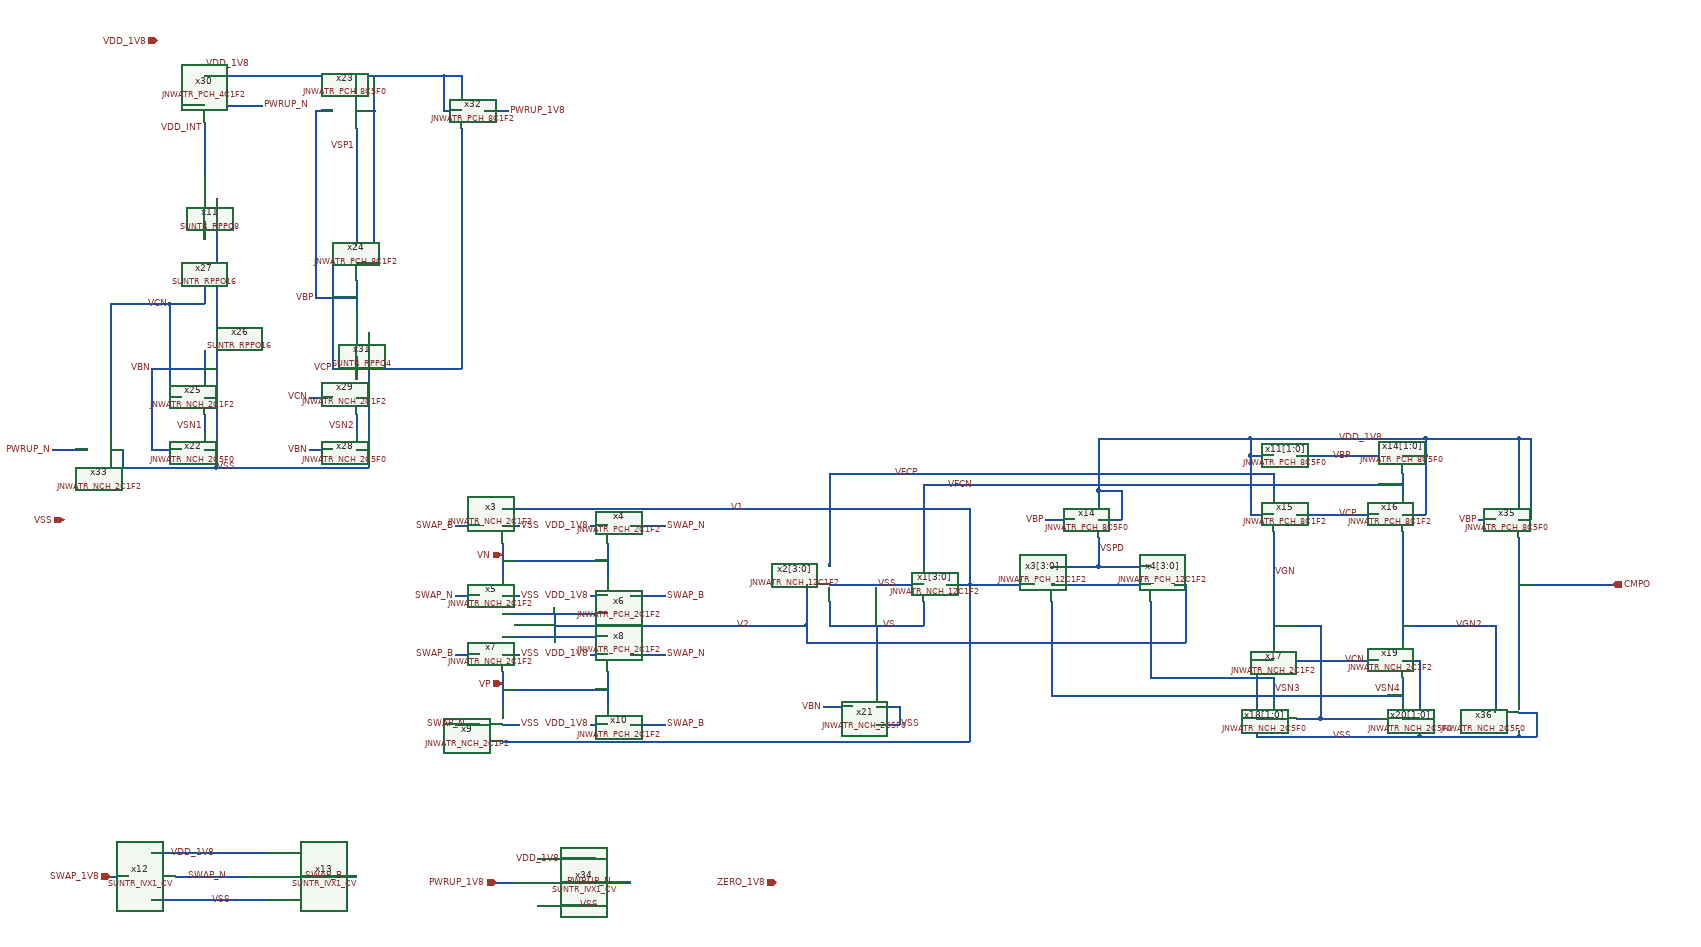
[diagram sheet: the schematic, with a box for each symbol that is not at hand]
v {xschem version=3.4.5 file_version=1.2
}
G {}
K {}
V {}
S {}
E {}
N 970 -730 1000 -730 {
lab=VSS}
N 1120 -730 1150 -730 {
lab=VDD_1V8}
N 890 -730 930 -730 {
lab=SWAP_B}
N 1190 -730 1250 -730 {
lab=SWAP_N}
N 970 -610 1000 -610 {
lab=VSS}
N 1120 -610 1150 -610 {
lab=VDD_1V8}
N 890 -610 930 -610 {
lab=SWAP_N}
N 1190 -610 1250 -610 {
lab=SWAP_B}
N 970 -700 970 -640 {
lab=VN}
N 1150 -700 1150 -640 {
lab=VN}
N 970 -580 1150 -580 {
lab=V2}
N 970 -760 1150 -760 {
lab=V1}
N 970 -510 1000 -510 {
lab=VSS}
N 1120 -510 1150 -510 {
lab=VDD_1V8}
N 890 -510 930 -510 {
lab=SWAP_B}
N 1190 -510 1250 -510 {
lab=SWAP_N}
N 970 -390 1000 -390 {
lab=VSS}
N 1120 -390 1150 -390 {
lab=VDD_1V8}
N 890 -390 930 -390 {
lab=SWAP_N}
N 1190 -390 1250 -390 {
lab=SWAP_B}
N 970 -480 970 -420 {
lab=VP}
N 1150 -480 1150 -420 {
lab=VP}
N 970 -360 1150 -360 {
lab=V1}
N 970 -540 1150 -540 {
lab=V2}
N 1060 -580 1060 -540 {
lab=V2}
N 1060 -560 1490 -560 {
lab=V2}
N 1490 -630 1490 -560 {
lab=V2}
N 1160 -760 1770 -760 {
lab=V1}
N 1770 -760 1770 -630 {
lab=V1}
N 1730 -630 1770 -630 {
lab=V1}
N 1150 -360 1770 -360 {
lab=V1}
N 1770 -630 1770 -360 {
lab=V1}
N 1530 -600 1530 -560 {
lab=VS}
N 1530 -560 1690 -560 {
lab=VS}
N 1690 -600 1690 -560 {
lab=VS}
N 370 -170 470 -170 {
lab=VDD_1V8}
N 370 -90 470 -90 {
lab=VSS}
N 410 -130 430 -130 {
lab=SWAP_N}
N 300 -130 330 -130 {
lab=SWAP_1V8}
N 470 -90 570 -90 {
lab=VSS}
N 470 -170 560 -170 {
lab=VDD_1V8}
N 430 -130 530 -130 {
lab=SWAP_N}
N 610 -130 720 -130 {
lab=SWAP_B}
N 970 -450 1150 -450 {
lab=VP}
N 970 -670 1150 -670 {
lab=VN}
N 1530 -630 1690 -630 {
lab=VSS}
N 2250 -850 2290 -850 {
lab=VDD_1V8}
N 2250 -880 2250 -850 {
lab=VDD_1V8}
N 2250 -880 2290 -880 {
lab=VDD_1V8}
N 2290 -880 2510 -880 {
lab=VDD_1V8}
N 2510 -850 2550 -850 {
lab=VDD_1V8}
N 2550 -880 2550 -850 {
lab=VDD_1V8}
N 2510 -880 2550 -880 {
lab=VDD_1V8}
N 2510 -820 2510 -780 {
lab=VFCN}
N 2290 -820 2290 -780 {
lab=VFCP}
N 2250 -750 2290 -750 {
lab=VDD_1V8}
N 2250 -850 2250 -750 {
lab=VDD_1V8}
N 2510 -750 2550 -750 {
lab=VDD_1V8}
N 2550 -850 2550 -750 {
lab=VDD_1V8}
N 2290 -470 2290 -430 {
lab=VSN3}
N 2260 -500 2290 -500 {
lab=VSS}
N 2260 -500 2260 -370 {
lab=VSS}
N 2260 -370 2290 -370 {
lab=VSS}
N 2260 -400 2290 -400 {
lab=VSS}
N 2510 -470 2510 -430 {
lab=VSN4}
N 2510 -500 2540 -500 {
lab=VSS}
N 2540 -500 2540 -370 {
lab=VSS}
N 2510 -370 2540 -370 {
lab=VSS}
N 2510 -400 2540 -400 {
lab=VSS}
N 2290 -720 2290 -530 {
lab=VGN}
N 2290 -370 2510 -370 {
lab=VSS}
N 1690 -800 1690 -660 {
lab=VFCN}
N 1690 -800 2130 -800 {
lab=VFCN}
N 1530 -820 1530 -660 {
lab=VFCP}
N 1530 -820 1910 -820 {
lab=VFCP}
N 2330 -400 2370 -400 {
lab=VGN}
N 2370 -560 2370 -400 {
lab=VGN}
N 2290 -560 2370 -560 {
lab=VGN}
N 2330 -500 2470 -500 {
lab=VCN}
N 2330 -750 2470 -750 {
lab=VCP}
N 2330 -850 2470 -850 {
lab=VBP}
N 1610 -560 1610 -450 {
lab=VS}
N 1610 -420 1650 -420 {
lab=VSS}
N 1650 -420 1650 -390 {
lab=VSS}
N 1610 -390 1650 -390 {
lab=VSS}
N 1520 -420 1570 -420 {
lab=VBN}
N 460 -920 460 -890 {
lab=VSN1}
N 460 -860 480 -860 {
lab=VSS}
N 480 -860 480 -830 {
lab=VSS}
N 460 -830 480 -830 {
lab=VSS}
N 480 -950 480 -860 {
lab=VSS}
N 460 -950 480 -950 {
lab=VSS}
N 460 -1030 460 -980 {
lab=VBN}
N 370 -860 420 -860 {
lab=VBN}
N 370 -1000 370 -860 {
lab=VBN}
N 370 -1000 460 -1000 {
lab=VBN}
N 400 -950 420 -950 {
lab=VCN}
N 400 -1110 400 -950 {
lab=VCN}
N 400 -1110 460 -1110 {
lab=VCN}
N 480 -1070 480 -950 {
lab=VSS}
N 480 -1180 480 -1070 {
lab=VSS}
N 460 -1140 460 -1110 {
lab=VCN}
N 420 -1450 460 -1450 {
lab=VDD_1V8}
N 420 -1480 420 -1450 {
lab=VDD_1V8}
N 420 -1480 460 -1480 {
lab=VDD_1V8}
N 460 -1520 460 -1480 {
lab=VDD_1V8}
N 500 -1450 560 -1450 {
lab=PWRUP_N}
N 720 -920 720 -890 {
lab=VSN2}
N 720 -950 740 -950 {
lab=VSS}
N 740 -950 740 -860 {
lab=VSS}
N 720 -860 740 -860 {
lab=VSS}
N 720 -830 740 -830 {
lab=VSS}
N 740 -860 740 -830 {
lab=VSS}
N 640 -950 680 -950 {
lab=VCN}
N 640 -860 680 -860 {
lab=VBN}
N 740 -1060 740 -950 {
lab=VSS}
N 720 -1020 720 -980 {
lab=VCP}
N 720 -1150 720 -1100 {
lab=VBP}
N 720 -1180 750 -1180 {
lab=VDD_1V8}
N 750 -1280 750 -1180 {
lab=VDD_1V8}
N 720 -1440 750 -1440 {
lab=VDD_1V8}
N 750 -1470 750 -1440 {
lab=VDD_1V8}
N 720 -1410 720 -1370 {
lab=VSP1}
N 680 -1180 680 -1000 {
lab=VCP}
N 680 -1000 720 -1000 {
lab=VCP}
N 650 -1120 720 -1120 {
lab=VBP}
N 650 -1280 650 -1120 {
lab=VBP}
N 650 -1440 680 -1440 {
lab=VBP}
N 460 -1500 720 -1500 {
lab=VDD_1V8}
N 720 -1500 720 -1470 {
lab=VDD_1V8}
N 900 -1260 900 -1000 {
lab=VCP}
N 720 -1000 900 -1000 {
lab=VCP}
N 870 -1440 900 -1440 {
lab=VDD_1V8}
N 870 -1500 870 -1440 {
lab=VDD_1V8}
N 870 -1500 900 -1500 {
lab=VDD_1V8}
N 900 -1500 900 -1470 {
lab=VDD_1V8}
N 720 -1500 870 -1500 {
lab=VDD_1V8}
N 940 -1440 980 -1440 {
lab=PWRUP_1V8}
N 300 -830 460 -830 {
lab=VSS}
N 300 -860 320 -860 {
lab=VSS}
N 320 -860 320 -830 {
lab=VSS}
N 300 -1110 300 -890 {
lab=VCN}
N 300 -1110 400 -1110 {
lab=VCN}
N 200 -860 260 -860 {
lab=PWRUP_N}
N 480 -830 720 -830 {
lab=VSS}
N 1030 -160 1130 -160 {
lab=VDD_1V8}
N 1030 -80 1130 -80 {
lab=VSS}
N 1070 -120 1090 -120 {
lab=PWRUP_N}
N 960 -120 990 -120 {
lab=PWRUP_1V8}
N 1090 -120 1190 -120 {
lab=PWRUP_N}
N 2370 -400 2470 -400 {
lab=VGN}
N 750 -1500 750 -1470 {
lab=VDD_1V8}
N 1150 -760 1160 -760 {
lab=V1}
N 560 -170 570 -170 {
lab=VDD_1V8}
N 750 -1440 750 -1280 {
lab=VDD_1V8}
N 720 -1370 720 -1210 {
lab=VSP1}
N 900 -1410 900 -1260 {
lab=VCP}
N 460 -1250 460 -1220 {
lab=#net1}
N 480 -1290 480 -1180 {
lab=VSS}
N 650 -1440 650 -1280 {
lab=VBP}
N 460 -1340 460 -1330 {
lab=VDD_INT}
N 460 -1420 460 -1400 {
lab=VDD_INT}
N 1910 -820 2290 -820 {
lab=VFCP}
N 2130 -800 2510 -800 {
lab=VFCN}
N 2510 -590 2510 -530 {
lab=VGN2}
N 2510 -720 2510 -670 {
lab=VGN2}
N 2710 -880 2710 -770 {
lab=VDD_1V8}
N 2550 -880 2710 -880 {
lab=VDD_1V8}
N 2710 -740 2730 -740 {
lab=VDD_1V8}
N 2730 -880 2730 -740 {
lab=VDD_1V8}
N 2710 -880 2730 -880 {
lab=VDD_1V8}
N 2710 -380 2710 -370 {
lab=VSS}
N 2540 -370 2710 -370 {
lab=VSS}
N 2710 -410 2740 -410 {
lab=VSS}
N 2740 -410 2740 -370 {
lab=VSS}
N 2710 -370 2740 -370 {
lab=VSS}
N 2710 -470 2710 -440 {
lab=CMPO}
N 2710 -710 2710 -470 {
lab=CMPO}
N 2710 -630 2870 -630 {
lab=CMPO}
N 2640 -740 2670 -740 {
lab=VBP}
N 2670 -560 2670 -410 {
lab=VGN2}
N 2510 -560 2670 -560 {
lab=VGN2}
N 2510 -670 2510 -590 {
lab=VGN2}
N 1990 -740 2030 -740 {
lab=VDD_1V8}
N 2030 -790 2030 -740 {
lab=VDD_1V8}
N 1990 -790 2030 -790 {
lab=VDD_1V8}
N 1990 -790 1990 -770 {
lab=VDD_1V8}
N 1990 -710 1990 -660 {
lab=VSPD}
N 1910 -660 1990 -660 {
lab=VSPD}
N 1990 -660 2080 -660 {
lab=VSPD}
N 1910 -630 2080 -630 {
lab=#net2}
N 2030 -880 2250 -880 {
lab=VDD_1V8}
N 2080 -600 2080 -470 {
lab=VSN3}
N 2080 -470 2290 -470 {
lab=VSN3}
N 1910 -600 1910 -440 {
lab=VSN4}
N 1910 -440 2510 -440 {
lab=VSN4}
N 1770 -630 1880 -630 {
lab=V1}
N 1490 -560 1490 -530 {
lab=V2}
N 1490 -530 2140 -530 {
lab=V2}
N 2120 -630 2140 -630 {
lab=V2}
N 2140 -630 2140 -530 {
lab=V2}
N 1900 -740 1950 -740 {
lab=VBP}
N 460 -1400 460 -1340 {
lab=VDD_INT}
N 1990 -880 1990 -790 {
lab=VDD_1V8}
N 1990 -880 2030 -880 {
lab=VDD_1V8}
C {JNW_ATR_SKY130NM/JNWATR_NCH_12C1F2.sym} 1490 -630 0 0 {name=x2[3:0]}
C {JNW_ATR_SKY130NM/JNWATR_NCH_12C1F2.sym} 1730 -630 0 1 {name=x1[3:0]}
C {JNW_ATR_SKY130NM/JNWATR_NCH_2C1F2.sym} 930 -730 0 0 {name=x3 }
C {JNW_ATR_SKY130NM/JNWATR_PCH_2C1F2.sym} 1190 -730 0 1 {name=x4 }
C {devices/lab_wire.sym} 1120 -730 0 0 {name=p1 sig_type=std_logic lab=VDD_1V8}
C {devices/lab_wire.sym} 1000 -730 0 1 {name=p2 sig_type=std_logic lab=VSS}
C {JNW_ATR_SKY130NM/JNWATR_NCH_2C1F2.sym} 930 -610 0 0 {name=x5 }
C {JNW_ATR_SKY130NM/JNWATR_PCH_2C1F2.sym} 1190 -610 0 1 {name=x6 }
C {devices/lab_wire.sym} 1120 -610 0 0 {name=p3 sig_type=std_logic lab=VDD_1V8}
C {devices/lab_wire.sym} 1000 -610 0 1 {name=p4 sig_type=std_logic lab=VSS}
C {JNW_ATR_SKY130NM/JNWATR_NCH_2C1F2.sym} 930 -510 0 0 {name=x7 }
C {JNW_ATR_SKY130NM/JNWATR_PCH_2C1F2.sym} 1190 -510 0 1 {name=x8 }
C {devices/lab_wire.sym} 1120 -510 0 0 {name=p5 sig_type=std_logic lab=VDD_1V8}
C {devices/lab_wire.sym} 1000 -510 0 1 {name=p6 sig_type=std_logic lab=VSS}
C {JNW_ATR_SKY130NM/JNWATR_NCH_2C1F2.sym} 930 -390 0 0 {name=x9 }
C {JNW_ATR_SKY130NM/JNWATR_PCH_2C1F2.sym} 1190 -390 0 1 {name=x10 }
C {devices/lab_wire.sym} 1120 -390 0 0 {name=p7 sig_type=std_logic lab=VDD_1V8}
C {devices/lab_wire.sym} 1000 -390 0 1 {name=p8 sig_type=std_logic lab=VSS}
C {devices/ipin.sym} 300 -130 0 0 {name=p10 lab=SWAP_1V8}
C {SUN_TR_SKY130NM/SUNTR_IVX1_CV.sym} 330 -130 0 0 {name=x12 }
C {SUN_TR_SKY130NM/SUNTR_IVX1_CV.sym} 530 -130 0 0 {name=x13 }
C {devices/lab_wire.sym} 480 -170 0 0 {name=p11 sig_type=std_logic lab=VDD_1V8}
C {devices/lab_wire.sym} 500 -130 0 0 {name=p12 sig_type=std_logic lab=SWAP_N}
C {devices/lab_wire.sym} 700 -130 0 0 {name=p13 sig_type=std_logic lab=SWAP_B}
C {devices/lab_wire.sym} 470 -90 0 1 {name=p14 sig_type=std_logic lab=VSS}
C {devices/lab_wire.sym} 910 -390 0 0 {name=p15 sig_type=std_logic lab=SWAP_N}
C {devices/lab_wire.sym} 1250 -390 0 1 {name=p16 sig_type=std_logic lab=SWAP_B}
C {devices/lab_wire.sym} 890 -730 0 0 {name=p18 sig_type=std_logic lab=SWAP_B}
C {devices/lab_wire.sym} 890 -510 0 0 {name=p19 sig_type=std_logic lab=SWAP_B}
C {devices/lab_wire.sym} 1250 -510 0 1 {name=p20 sig_type=std_logic lab=SWAP_N}
C {devices/lab_wire.sym} 1250 -610 0 1 {name=p21 sig_type=std_logic lab=SWAP_B}
C {devices/lab_wire.sym} 890 -610 0 0 {name=p22 sig_type=std_logic lab=SWAP_N}
C {devices/lab_wire.sym} 1250 -730 0 1 {name=p17 sig_type=std_logic lab=SWAP_N}
C {devices/lab_wire.sym} 1360 -760 0 1 {name=p23 sig_type=std_logic lab=V1}
C {devices/lab_wire.sym} 1370 -560 0 1 {name=p24 sig_type=std_logic lab=V2}
C {devices/ipin.sym} 970 -680 0 0 {name=p25 lab=VN}
C {devices/ipin.sym} 970 -460 0 0 {name=p26 lab=VP}
C {JNW_ATR_SKY130NM/JNWATR_PCH_8C5F0.sym} 2330 -850 0 1 {name=x11[1:0]}
C {JNW_ATR_SKY130NM/JNWATR_PCH_8C5F0.sym} 2470 -850 0 0 {name=x14[1:0]}
C {JNW_ATR_SKY130NM/JNWATR_PCH_8C1F2.sym} 2330 -750 0 1 {name=x15 }
C {JNW_ATR_SKY130NM/JNWATR_PCH_8C1F2.sym} 2470 -750 0 0 {name=x16 }
C {JNW_ATR_SKY130NM/JNWATR_NCH_2C1F2.sym} 2330 -500 0 1 {name=x17 }
C {JNW_ATR_SKY130NM/JNWATR_NCH_2C5F0.sym} 2330 -400 0 1 {name=x18[1:0]}
C {JNW_ATR_SKY130NM/JNWATR_NCH_2C1F2.sym} 2470 -500 0 0 {name=x19 }
C {JNW_ATR_SKY130NM/JNWATR_NCH_2C5F0.sym} 2470 -400 0 0 {name=x20[1:0]}
C {devices/lab_wire.sym} 2390 -370 0 1 {name=p9 sig_type=std_logic lab=VSS}
C {devices/lab_wire.sym} 2400 -880 0 1 {name=p27 sig_type=std_logic lab=VDD_1V8}
C {devices/lab_wire.sym} 2410 -500 0 1 {name=p28 sig_type=std_logic lab=VCN}
C {devices/lab_wire.sym} 2400 -750 0 1 {name=p29 sig_type=std_logic lab=VCP}
C {devices/lab_wire.sym} 2390 -850 0 1 {name=p30 sig_type=std_logic lab=VBP}
C {JNW_ATR_SKY130NM/JNWATR_NCH_2C5F0.sym} 1570 -420 0 0 {name=x21 }
C {devices/lab_wire.sym} 1650 -390 0 1 {name=p31 sig_type=std_logic lab=VSS}
C {devices/lab_wire.sym} 1520 -420 0 0 {name=p32 sig_type=std_logic lab=VBN}
C {JNW_ATR_SKY130NM/JNWATR_NCH_2C5F0.sym} 420 -860 0 0 {name=x22 }
C {JNW_ATR_SKY130NM/JNWATR_PCH_8C5F0.sym} 680 -1440 0 0 {name=x23 }
C {JNW_ATR_SKY130NM/JNWATR_PCH_8C1F2.sym} 680 -1180 0 0 {name=x24 }
C {JNW_ATR_SKY130NM/JNWATR_NCH_2C1F2.sym} 420 -950 0 0 {name=x25 }
C {SUN_TR_SKY130NM/SUNTR_RPPO16.sym} 460 -1030 3 0 {name=x26 }
C {SUN_TR_SKY130NM/SUNTR_RPPO16.sym} 460 -1140 3 0 {name=x27 }
C {devices/lab_wire.sym} 460 -1520 0 1 {name=p33 sig_type=std_logic lab=VDD_1V8}
C {devices/lab_wire.sym} 480 -830 0 1 {name=p34 sig_type=std_logic lab=VSS}
C {JNW_ATR_SKY130NM/JNWATR_NCH_2C5F0.sym} 680 -860 0 0 {name=x28 }
C {JNW_ATR_SKY130NM/JNWATR_NCH_2C1F2.sym} 680 -950 0 0 {name=x29 }
C {JNW_ATR_SKY130NM/JNWATR_PCH_4C1F2.sym} 500 -1450 0 1 {name=x30 }
C {devices/lab_wire.sym} 560 -1450 0 1 {name=p35 sig_type=std_logic lab=PWRUP_N}
C {devices/lab_wire.sym} 370 -1000 0 0 {name=p36 sig_type=std_logic lab=VBN}
C {devices/lab_wire.sym} 400 -1110 0 0 {name=p37 sig_type=std_logic lab=VCN}
C {devices/lab_wire.sym} 640 -950 0 0 {name=p38 sig_type=std_logic lab=VCN}
C {devices/lab_wire.sym} 640 -860 0 0 {name=p39 sig_type=std_logic lab=VBN}
C {SUN_TR_SKY130NM/SUNTR_RPPO4.sym} 720 -1020 3 0 {name=x31 }
C {devices/lab_wire.sym} 680 -1000 0 0 {name=p40 sig_type=std_logic lab=VCP}
C {devices/lab_wire.sym} 650 -1120 0 0 {name=p41 sig_type=std_logic lab=VBP}
C {JNW_ATR_SKY130NM/JNWATR_PCH_8C1F2.sym} 940 -1440 0 1 {name=x32 }
C {devices/lab_wire.sym} 980 -1440 0 1 {name=p42 sig_type=std_logic lab=PWRUP_1V8}
C {JNW_ATR_SKY130NM/JNWATR_NCH_2C1F2.sym} 260 -860 0 0 {name=x33 }
C {devices/lab_wire.sym} 200 -860 0 0 {name=p43 sig_type=std_logic lab=PWRUP_N}
C {devices/ipin.sym} 220 -740 0 0 {name=p45 lab=VSS}
C {devices/ipin.sym} 1440 -120 0 0 {name=p46 lab=ZERO_1V8}
C {devices/ipin.sym} 960 -120 0 0 {name=p47 lab=PWRUP_1V8}
C {SUN_TR_SKY130NM/SUNTR_IVX1_CV.sym} 990 -120 0 0 {name=x34 }
C {devices/lab_wire.sym} 1070 -160 0 0 {name=p48 sig_type=std_logic lab=VDD_1V8}
C {devices/lab_wire.sym} 1160 -120 0 0 {name=p49 sig_type=std_logic lab=PWRUP_N}
C {devices/lab_wire.sym} 1100 -80 0 1 {name=p51 sig_type=std_logic lab=VSS}
C {devices/opin.sym} 2870 -630 0 0 {name=p50 lab=CMPO
}
C {devices/ipin.sym} 380 -1560 0 0 {name=p44 lab=VDD_1V8}
C {devices/lab_wire.sym} 1610 -630 0 1 {name=p52 sig_type=std_logic lab=VSS}
C {devices/lab_wire.sym} 460 -900 0 0 {name=p53 sig_type=std_logic lab=VSN1}
C {devices/lab_wire.sym} 720 -900 0 0 {name=p54 sig_type=std_logic lab=VSN2}
C {devices/lab_wire.sym} 720 -1380 0 0 {name=p55 sig_type=std_logic lab=VSP1}
C {devices/lab_wire.sym} 1620 -560 0 1 {name=p56 sig_type=std_logic lab=VS}
C {devices/lab_wire.sym} 460 -1410 0 0 {name=p57 sig_type=std_logic lab=VDD_INT}
C {devices/lab_wire.sym} 1640 -820 0 1 {name=p58 sig_type=std_logic lab=VFCP}
C {devices/lab_wire.sym} 1730 -800 0 1 {name=p59 sig_type=std_logic lab=VFCN}
C {devices/lab_wire.sym} 2290 -650 0 1 {name=p60 sig_type=std_logic lab=VGN}
C {devices/lab_wire.sym} 2290 -450 0 1 {name=p61 sig_type=std_logic lab=VSN3}
C {devices/lab_wire.sym} 2510 -450 0 0 {name=p62 sig_type=std_logic lab=VSN4}
C {SUN_TR_SKY130NM/SUNTR_RPPO8.sym} 460 -1250 3 0 {name=x11 }
C {JNW_ATR_SKY130NM/JNWATR_PCH_8C5F0.sym} 2670 -740 0 0 {name=x35 }
C {JNW_ATR_SKY130NM/JNWATR_NCH_2C5F0.sym} 2670 -410 0 0 {name=x36 }
C {devices/lab_wire.sym} 2600 -560 0 1 {name=p64 sig_type=std_logic lab=VGN2}
C {devices/lab_wire.sym} 2640 -740 0 0 {name=p63 sig_type=std_logic lab=VBP}
C {JNW_ATR_SKY130NM/JNWATR_PCH_12C1F2.sym} 1870 -630 0 0 {name=x3[3:0]}
C {JNW_ATR_SKY130NM/JNWATR_PCH_12C1F2.sym} 2120 -630 0 1 {name=x4[3:0]}
C {JNW_ATR_SKY130NM/JNWATR_PCH_8C5F0.sym} 1950 -740 0 0 {name=x14}
C {devices/lab_wire.sym} 1900 -740 0 0 {name=p65 sig_type=std_logic lab=VBP}
C {devices/lab_wire.sym} 1990 -690 0 1 {name=p66 sig_type=std_logic lab=VSPD}
